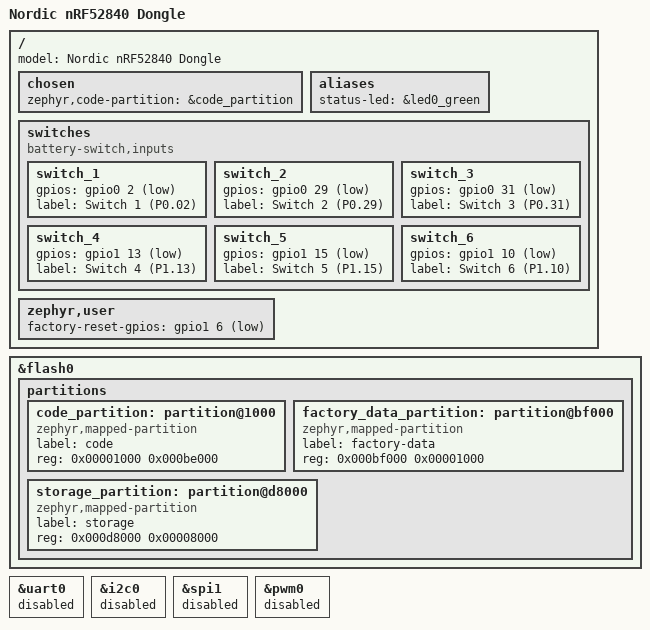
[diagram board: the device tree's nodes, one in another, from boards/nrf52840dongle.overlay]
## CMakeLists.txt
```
#
# SPDX-License-Identifier: MIT
#

cmake_minimum_required(VERSION 3.20.0)

find_package(Zephyr HINTS $ENV{ZEPHYR_BASE})

project(battery-switch)

target_include_directories(app PRIVATE src)

# Board name (devicetree model), shown as the hardware version by Matter
# controllers. Root node properties aren't exported to CMake, so it is read
# from the generated devicetree.
file(STRINGS ${ZEPHYR_DTS} board_model REGEX "^\tmodel = \"" LIMIT_COUNT 1)
string(REGEX REPLACE "^\tmodel = \"([^\"]*)\".*" "\\1" board_model "${board_model}")
target_compile_definitions(app PRIVATE "APP_BOARD_NAME=\"${board_model}\"")

# Transport-independent core: switch inputs, gesture detection, battery, LED.
target_sources(app PRIVATE
  src/main.c
  src/core/app_loop.c
  src/core/battery.c
  src/core/reset_pin.c
  src/core/switch_config.c
  src/core/status_led.c
  src/core/switch_gesture.c
  src/core/switch_input.c
)

target_sources_ifdef(CONFIG_APP_USB_INFO app PRIVATE
  src/core/usb_info.c
  src/third_party/qrcodegen/qrcodegen.c
)
target_sources_ifdef(CONFIG_APP_USB_BOOTLOADER_RESET app PRIVATE src/core/usb_bootloader.c)
target_sources_ifdef(CONFIG_APP_TRANSPORT_BLE app PRIVATE src/transport/ble/ble_transport.c)

if(CONFIG_APP_TRANSPORT_MATTER)
  include(${ZEPHYR_CONNECTEDHOMEIP_MODULE_DIR}/config/nrfconnect/app/enable-gnu-std.cmake)
  include(${ZEPHYR_NRF_MODULE_DIR}/samples/matter/common/cmake/data_model.cmake)
  include(${ZEPHYR_NRF_MODULE_DIR}/samples/matter/common/cmake/zap_helpers.cmake)
  ncs_get_zap_parent_dir(ZAP_PARENT_DIR)

  # Only the parts of the nRF Matter sample commons that do not depend on the
  # DK buttons/LEDs library.
  set(MATTER_COMMONS_SRC_DIR ${ZEPHYR_NRF_MODULE_DIR}/samples/matter/common/src)

  target_include_directories(app PRIVATE
    ${MATTER_COMMONS_SRC_DIR}
    ${ZAP_PARENT_DIR}
  )

  target_sources(app PRIVATE
    ${MATTER_COMMONS_SRC_DIR}/app/matter_init.cpp
    ${MATTER_COMMONS_SRC_DIR}/app/matter_event_handler.cpp
    ${MATTER_COMMONS_SRC_DIR}/clusters/cluster_init.cpp
    src/transport/matter/matter_transport.cpp
  )
  target_sources_ifdef(CONFIG_CHIP_FACTORY_DATA app PRIVATE src/transport/matter/self_provision.cpp)

  zephyr_linker_sources(SECTIONS ${MATTER_COMMONS_SRC_DIR}/clusters/cluster_init.ld)

  ncs_configure_data_model()
endif()
```

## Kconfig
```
#
# SPDX-License-Identifier: MIT
#

mainmenu "Battery powered switch"

menu "Battery switch application"

choice APP_TRANSPORT
	prompt "Radio transport"
	default APP_TRANSPORT_MATTER
	help
	  Selects the protocol used to report switch events and battery state.
	  The switch/battery core in src/core does not depend on the transport;
	  a new transport only has to implement src/transport/transport.h.

config APP_TRANSPORT_MATTER
	bool "Matter over Thread"
	help
	  Requires SB_CONFIG_MATTER=y in sysbuild.conf. Every switch is exposed
	  as a Generic Switch endpoint (1..6), the battery as a Power Source
	  cluster on endpoint 0.

config APP_TRANSPORT_BLE
	bool "Bluetooth LE (GATT)"
	select BT
	select BT_PERIPHERAL
	select BT_BAS
	select REBOOT
	help
	  Connectable peripheral that notifies switch events over a custom
	  GATT service, battery level over the Battery Service. Mainly for
	  testing without a Thread network; see src/transport/ble/ and
	  tools/ble_test_client.py. Build with -DFILE_SUFFIX=ble.

endchoice

config APP_BLE_ADV_INTERVAL_MS
	int "BLE advertising interval [ms]"
	depends on APP_TRANSPORT_BLE
	default 1000
	range 20 10000

menu "Switch inputs"

config APP_DEBOUNCE_MS
	int "Momentary switch: debounce time [ms]"
	default 20
	range 1 200

config APP_DEBOUNCE_LATCHING_MS
	int "Latching switch: debounce time [ms]"
	default 20
	range 1 500
	help
	  Debounce time for latching switches. They report every bounce
	  that outlasts the debounce time as an extra press, so noisy
	  contacts may need more than momentary switches. Nobody flips a
	  switch twice within 100 ms, so values up to that cost no
	  responsiveness.

config APP_LONG_PRESS_MS
	int "Momentary switch: hold time for a long press [ms]"
	default 1000
	range 200 10000

config APP_MULTI_PRESS_WINDOW_MS
	int "Momentary switch: max. gap between presses of a multi-press [ms]"
	default 400
	range 100 2000
	help
	  After the last release, MultiPressComplete is reported once no new
	  press started within this window. Larger values make double presses
	  easier, but delay the single press report by the same amount.

config APP_MULTI_PRESS_MAX
	int "Momentary switch: maximum number of presses in a multi-press"
	default 2
	range 2 10

config APP_LATCH_POLL_INTERVAL_MS
	int "Latching switch: poll interval while the switch is closed [ms]"
	default 100
	range 10 2000
	help
	  A closed switch would permanently draw current through the pull-up
	  resistor (~230 uA at 3 V with the internal 13 kOhm pull-up). While a
	  latching switch is closed, its pin is
	  disconnected and only briefly sampled at this interval. This is the
	  worst case latency for detecting the switch being opened.

config APP_LATCH_POLL_SETTLE_US
	int "Latching switch: pull-up settle time before sampling [us]"
	default 10
	range 1 1000
	help
	  Increase for long cables between the board and the switch.

endmenu

menu "Battery"

choice APP_BATTERY_TYPE
	prompt "Battery type"
	default APP_BATTERY_2XAAA_ALKALINE
	help
	  Selects the voltage-to-charge curve used for the reported battery
	  percentage. The battery is expected to be connected to the 3V3 pin
	  (the nRF52840 supply), so no voltage divider is needed.

config APP_BATTERY_CR2032
	bool "CR2032 lithium coin cell (3 V)"

config APP_BATTERY_2XAAA_ALKALINE
	bool "2x AAA alkaline in series"

config APP_BATTERY_2XAAA_CARBON_ZINC
	bool "2x AAA carbon-zinc in series"

config APP_BATTERY_2XAAA_NIMH
	bool "2x AAA NiMH in series"

endchoice

config APP_BATTERY_MEASURE_INTERVAL_S
	int "Battery measurement interval [s]"
	default 3600
	range 60 86400

config APP_BATTERY_WARNING_PERCENT
	int "Report charge level 'Warning' at or below [%]"
	default 20
	range 0 100

config APP_BATTERY_CRITICAL_PERCENT
	int "Report charge level 'Critical' (replace battery) at or below [%]"
	default 5
	range 0 100

endmenu

menu "User interface"

config APP_STATUS_LED
	bool "Status LED"
	default y
	help
	  Uses the devicetree alias 'status-led' for pairing, identify and
	  factory reset feedback. Blinks are short to save power.

config APP_BOOT_FLASHES
	int "Status LED: flashes at startup"
	depends on APP_STATUS_LED
	default 3
	range 0 10
	help
	  Quick flashes when the firmware starts, as a sign of life after
	  inserting the battery or flashing. 0 disables them.

config APP_PRODUCT_NAME
	string "Product name shown on the USB serial port"
	default "Battery Switch"

config APP_USB_INFO
	bool "Show the pairing code on the USB serial port"
	depends on USBD_CDC_ACM_CLASS && UART_LINE_CTRL
	depends on !CDC_ACM_SERIAL_INITIALIZE_AT_BOOT
	default y
	help
	  When a terminal opens the USB serial port, print the pairing code
	  and QR code. USB is only enabled while USB power is present, so it
	  costs no current on battery. Not available with the USB console
	  (usb-logging.conf), which logs the pairing code instead.

config APP_FACTORY_RESET_HOLD_MS
	int "Reset pad: hold time for factory reset [ms]"
	default 5000
	range 1000 60000
	help
	  The factory reset pad (devicetree: `factory-reset-gpios` in the
	  `zephyr,user` node) has to be held to GND continuously for this
	  long. The pad is separate from the switch inputs, so no switch
	  gesture can trigger a reset.

endmenu

config APP_USB_BOOTLOADER_RESET
	bool "Reboot into the bootloader on a 1200 baud USB touch"
	depends on USB_DEVICE_STACK_NEXT && UART_LINE_CTRL
	help
	  Development helper for builds with the USB console
	  (usb-logging.conf). Opening and closing the USB serial port at
	  1200 baud reboots into the Adafruit bootloader, so the board can be
	  reflashed without pressing reset.

choice APP_USB_BOOTLOADER_MODE
	prompt "Bootloader mode entered on a 1200 baud touch"
	depends on APP_USB_BOOTLOADER_RESET
	default APP_USB_BOOTLOADER_MODE_SERIAL

config APP_USB_BOOTLOADER_MODE_SERIAL
	bool "Serial DFU only"
	help
	  For adafruit-nrfutil, which sends the touch itself:
	    adafruit-nrfutil dfu serial --touch 1200 --singlebank ...
	  More reliable than the USB drive on macOS, which can hang when
	  copying large UF2 files.

config APP_USB_BOOTLOADER_MODE_UF2
	bool "UF2 USB drive"

endchoice

config APP_EVENT_QUEUE_SIZE
	int "Application event queue size"
	default 16

endmenu

# Matter over Thread defaults (same pattern as the nRF Connect SDK Matter
# samples). They only take effect when CONFIG_CHIP is enabled.

# Sleepy end device: the radio is off except for polling the parent.
choice OPENTHREAD_NORDIC_LIBRARY_CONFIGURATION
	default OPENTHREAD_NORDIC_LIBRARY_MTD
endchoice

choice OPENTHREAD_DEVICE_TYPE
	default OPENTHREAD_MTD
endchoice

config CHIP_ENABLE_ICD_SUPPORT
	default y

config CHIP_ICD_LIT_SUPPORT
	default y

config CHIP_ICD_SIT_SLOW_POLL_LIMIT
	default 5000

config CHIP_ICD_REPORT_ON_ACTIVE_MODE
	default y

# 0 dBm is plenty for an end device next to its parent and keeps the TX peak
# current low, which matters for coin cells.
config OPENTHREAD_DEFAULT_TX_POWER
	default 0

source "$(ZEPHYR_CONNECTEDHOMEIP_MODULE_DIR)/config/nrfconnect/chip-module/Kconfig.features"
source "$(ZEPHYR_CONNECTEDHOMEIP_MODULE_DIR)/config/nrfconnect/chip-module/Kconfig.defaults"
source "$(ZEPHYR_NRF_MODULE_DIR)/samples/matter/common/src/Kconfig"

source "Kconfig.zephyr"
```

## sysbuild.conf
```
SB_CONFIG_MATTER=y
SB_CONFIG_PARTITION_MANAGER=n

# Barebones: no MCUboot and no Matter OTA. The board's Adafruit UF2 bootloader
# stays in place (see boards/xiao_ble.overlay and sysbuild.cmake).
SB_CONFIG_MATTER_OTA=n

# Don't generate factory data in the build: it would give every device the
# same, publicly known Matter test passcode (20202021). Each device gets its
# own credentials from tools/provision_device.py instead.
SB_CONFIG_MATTER_FACTORY_DATA_GENERATE=n
```

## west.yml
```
# West manifest for a workspace application.
#
#   west init -m https://github.com/<you>/nrf52840-battery-button --mr main battery-switch-ws
#   cd battery-switch-ws && west update
#
# This pulls nRF Connect SDK v3.4.1 (Zephyr, OpenThread, Matter) next to this repository.

manifest:
  version: "0.13"

  remotes:
    - name: ncs
      url-base: https://github.com/nrfconnect

  projects:
    - name: nrf
      remote: ncs
      repo-path: sdk-nrf
      revision: v3.4.1
      import: true

  self:
    path: nrf52840-battery-button
```

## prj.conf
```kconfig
#
# Low-power configuration (default). For logs over SEGGER RTT build with
#   west build ... -- -DEXTRA_CONF_FILE=debug.conf
#

# ---------------------------------------------------------------------------
# Matter
# ---------------------------------------------------------------------------
CONFIG_CHIP=y
CONFIG_CHIP_PROJECT_CONFIG="src/chip_project_config.h"
CONFIG_CHIP_DEVICE_PRODUCT_NAME="Battery Switch"
CONFIG_NCS_SAMPLE_MATTER_ZAP_FILE_PATH="${APPLICATION_CONFIG_DIR}/src/default_zap/battery_switch.zap"

# Test Vendor ID / Product ID (0xFFF1 / 0x8000). Replace for a real product.
CONFIG_CHIP_DEVICE_PRODUCT_ID=32768
CONFIG_STD_CPP17=y

# Start BLE commissioning advertising on boot while not commissioned.
# Afterwards, pressing any switch restarts it.
CONFIG_CHIP_ENABLE_PAIRING_AUTOSTART=y
CONFIG_CHIP_BLE_EXT_ADVERTISING=y
CONFIG_CHIP_BLE_ADVERTISING_DURATION=15

CONFIG_BT_DEVICE_NAME="MatterSwitch"
CONFIG_BT_DEVICE_NAME_MAX=18

# Onboarding credentials come from the factory data partition, written per
# device by tools/provision_device.py (not generated by the build).
CONFIG_CHIP_FACTORY_DATA=y
CONFIG_CHIP_FACTORY_DATA_BUILD=n

# First boot computes the SPAKE2+ verifier on the device
# (src/transport/matter/self_provision.cpp).
CONFIG_PSA_WANT_ALG_PBKDF2_HMAC=y
CONFIG_PSA_WANT_KEY_TYPE_PASSWORD=y
CONFIG_PSA_WANT_KEY_TYPE_SPAKE2P_KEY_PAIR_DERIVE=y
CONFIG_PSA_WANT_KEY_TYPE_SPAKE2P_KEY_PAIR_EXPORT=y

# No MCUboot (see sysbuild.conf).
CONFIG_CHIP_BOOTLOADER_NONE=y

# The XIAO has no NFC antenna.
CONFIG_CHIP_NFC_ONBOARDING_PAYLOAD=n

# Parts of the nRF Matter sample commons that are not used.
CONFIG_NCS_SAMPLE_MATTER_TEST_EVENT_TRIGGERS=n
CONFIG_CHIP_LIB_SHELL=n

# ---------------------------------------------------------------------------
# Hardware
# ---------------------------------------------------------------------------
CONFIG_GPIO=y
CONFIG_ADC=y
CONFIG_FLASH=y

# The board's UF2 output would contain only the application. sysbuild.cmake
# builds build/battery_switch.uf2 with the Matter factory data included.
CONFIG_BUILD_OUTPUT_UF2=n

# Link at the application partition from devicetree (0x26000/0x27000 on UF2
# bootloader boards). Not every board's UF2 target sets this.
CONFIG_USE_DT_CODE_PARTITION=y

# ---------------------------------------------------------------------------
# Power
# ---------------------------------------------------------------------------
CONFIG_PM_DEVICE=y
CONFIG_RAM_POWER_DOWN_LIBRARY=y

# USB serial port that only shows the pairing code (src/core/usb_info.c),
# not a console. USB is only enabled while USB power is present.
CONFIG_BOARD_SERIAL_BACKEND_CDC_ACM=n
CONFIG_SERIAL=y
CONFIG_USB_DEVICE_STACK_NEXT=y
CONFIG_USBD_CDC_ACM_CLASS=y
CONFIG_UART_LINE_CTRL=y
CONFIG_CONSOLE=n
CONFIG_UART_CONSOLE=n
CONFIG_USE_SEGGER_RTT=n
CONFIG_LOG=n
CONFIG_PRINTK=n
CONFIG_SHELL=n
CONFIG_OPENTHREAD_SHELL=n
CONFIG_BOOT_BANNER=n
CONFIG_NCS_BOOT_BANNER=n
CONFIG_THREAD_NAME=n

CONFIG_ASSERT_VERBOSE=n
CONFIG_ASSERT_NO_FILE_INFO=y
CONFIG_RESET_ON_FATAL_ERROR=y

# Reduce flash usage.
CONFIG_LTO=y
CONFIG_ISR_TABLES_LOCAL_DECLARATION=y
```

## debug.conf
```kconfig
#
# Debug overlay: logs and printk over SEGGER RTT (needs the SWD probe).
#   west build -b xiao_ble/nrf52840 --sysbuild -- -DEXTRA_CONF_FILE=debug.conf
#
CONFIG_LOG=y
CONFIG_PRINTK=y
CONFIG_CONSOLE=y
CONFIG_USE_SEGGER_RTT=y
CONFIG_RTT_CONSOLE=y
CONFIG_NCS_BOOT_BANNER=y
CONFIG_THREAD_NAME=y
CONFIG_RESET_ON_FATAL_ERROR=n
```

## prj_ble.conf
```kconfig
#
# Bluetooth LE transport (for testing without a Thread network):
#   west build -b xiao_ble/nrf52840 --sysbuild -- -DFILE_SUFFIX=ble
# This file replaces prj.conf and sysbuild_ble.conf replaces sysbuild.conf.
#

CONFIG_APP_TRANSPORT_BLE=y

CONFIG_BT_DEVICE_NAME="BatterySwitch"
# Appearance: Generic Remote Control.
CONFIG_BT_DEVICE_APPEARANCE=384
CONFIG_BT_MAX_CONN=1

# ---------------------------------------------------------------------------
# Hardware
# ---------------------------------------------------------------------------
CONFIG_GPIO=y
CONFIG_ADC=y
CONFIG_FLASH=y

# Switch types changed over BLE are stored in the settings partition.
CONFIG_FLASH_MAP=y
CONFIG_NVS=y
CONFIG_SETTINGS=y

# sysbuild.cmake builds build/battery_switch.uf2.
CONFIG_BUILD_OUTPUT_UF2=n

# Link at the application partition from devicetree (0x26000/0x27000 on UF2
# bootloader boards). Not every board's UF2 target sets this.
CONFIG_USE_DT_CODE_PARTITION=y

# ---------------------------------------------------------------------------
# Power
# ---------------------------------------------------------------------------
CONFIG_PM_DEVICE=y

# No USB console by default. Add usb-logging.conf/.overlay for development.
CONFIG_BOARD_SERIAL_BACKEND_CDC_ACM=n
CONFIG_SERIAL=n
CONFIG_CONSOLE=n
CONFIG_UART_CONSOLE=n
CONFIG_USE_SEGGER_RTT=n
CONFIG_LOG=n
CONFIG_PRINTK=n
CONFIG_BOOT_BANNER=n
CONFIG_NCS_BOOT_BANNER=n

CONFIG_ASSERT_VERBOSE=n
CONFIG_ASSERT_NO_FILE_INFO=y
CONFIG_RESET_ON_FATAL_ERROR=y
```

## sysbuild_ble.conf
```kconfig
# Bluetooth LE build: no Matter, no factory data, no bootloader besides the
# board's UF2 bootloader.
SB_CONFIG_PARTITION_MANAGER=n
```

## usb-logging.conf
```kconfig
#
# Development overlay: log to the USB serial port and allow reflashing via a
# 1200 baud touch:
#   west build ... -- -DEXTRA_CONF_FILE=usb-logging.conf
# USB draws power; not for battery operation.
#
CONFIG_BOARD_SERIAL_BACKEND_CDC_ACM=y
CONFIG_SERIAL=y
CONFIG_CONSOLE=y
CONFIG_UART_CONSOLE=y
CONFIG_UART_LINE_CTRL=y
CONFIG_LOG=y
CONFIG_PRINTK=y
CONFIG_NCS_BOOT_BANNER=y
CONFIG_RESET_ON_FATAL_ERROR=n
CONFIG_APP_USB_BOOTLOADER_RESET=y
```

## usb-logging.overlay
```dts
/* Re-enable USB for usb-logging.conf (the board overlay disables it). */
&usbd {
	status = "okay";
};
```

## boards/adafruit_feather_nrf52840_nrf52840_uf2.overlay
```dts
/*
 * SPDX-License-Identifier: MIT
 *
 * Adafruit Feather nRF52840 Express: adafruit_feather_nrf52840/nrf52840/uf2.
 * The image also runs on the Feather nRF52840 Sense (same pins, the blue
 * LED is the same). Build-tested only.
 *
 * Switch wiring: every switch goes between its pin and GND.
 *
 *   Switch 1 -> A0 (P0.04)      Switch 4 -> A3 (P0.28)
 *   Switch 2 -> A1 (P0.05)      Switch 5 -> A4 (P0.02)
 *   Switch 3 -> A2 (P0.30)      Switch 6 -> A5 (P0.03)
 *
 * Factory reset: hold the board's USER button for 5 s.
 *
 * Battery: connect + to 3V and - to GND (2x AAA or CR2032), not to the LiPo
 * connector: the battery voltage is measured on the nRF52840 VDD rail.
 */

/ {
	aliases {
		status-led = &led1; /* blue */
	};

	switches {
		compatible = "battery-switch,inputs";

		switch_1 {
			gpios = <&gpio0 4 (GPIO_PULL_UP | GPIO_ACTIVE_LOW)>;
			label = "Switch 1 (A0)";
		};

		switch_2 {
			gpios = <&gpio0 5 (GPIO_PULL_UP | GPIO_ACTIVE_LOW)>;
			label = "Switch 2 (A1)";
		};

		switch_3 {
			gpios = <&gpio0 30 (GPIO_PULL_UP | GPIO_ACTIVE_LOW)>;
			label = "Switch 3 (A2)";
		};

		switch_4 {
			gpios = <&gpio0 28 (GPIO_PULL_UP | GPIO_ACTIVE_LOW)>;
			label = "Switch 4 (A3)";
		};

		switch_5 {
			gpios = <&gpio0 2 (GPIO_PULL_UP | GPIO_ACTIVE_LOW)>;
			label = "Switch 5 (A4)";
		};

		switch_6 {
			gpios = <&gpio0 3 (GPIO_PULL_UP | GPIO_ACTIVE_LOW)>;
			label = "Switch 6 (A5)";
		};
	};

	zephyr,user {
		/* USER button (P1.02), inside the enclosure. */
		factory-reset-gpios = <&gpio1 2 (GPIO_PULL_UP | GPIO_ACTIVE_LOW)>;
	};
};

/* The Feather ships with SoftDevice S140 v6: the application starts at 0x26000. */
#define UF2_APP_START 0x26000
#include "uf2_matter_layout.dtsi"

/* Peripherals that are not used; disabling them avoids idle current. */
&uart0 {
	status = "disabled";
};

&i2c0 {
	status = "disabled";
};

&spi1 {
	status = "disabled";
};

#include "battery_switch_common.dtsi"
```

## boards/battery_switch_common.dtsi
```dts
/*
 * SPDX-License-Identifier: MIT
 *
 * Parts shared by all board overlays. Include it at the end of the overlay.
 */

#include <zephyr/dt-bindings/adc/nrf-saadc.h>

/ {
	zephyr,user {
		io-channels = <&adc 0>;
	};
};

/* Battery voltage = nRF52840 VDD (battery connected to the 3V3 pin). */
&adc {
	#address-cells = <1>;
	#size-cells = <0>;
	status = "okay";

	channel@0 {
		reg = <0>;
		zephyr,gain = "ADC_GAIN_1_6";
		zephyr,reference = "ADC_REF_INTERNAL";
		zephyr,acquisition-time = <ADC_ACQ_TIME(ADC_ACQ_TIME_MICROSECONDS, 10)>;
		zephyr,input-positive = <NRF_SAADC_VDD>;
		zephyr,resolution = <12>;
		zephyr,oversampling = <4>;
	};
};

/*
 * USB serial port showing the pairing code (src/core/usb_info.c). USB is
 * only enabled while USB power is present. The output fits into the TX
 * FIFO, so a terminal that stops reading can't block the application.
 */
&board_cdc_acm_uart {
	tx-fifo-size = <2048>;
	rx-fifo-size = <64>;
};
```

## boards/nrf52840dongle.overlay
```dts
/*
 * SPDX-License-Identifier: MIT
 *
 * Nordic nRF52840 Dongle (PCA10059): nrf52840dongle/nrf52840.
 * Advanced, at your own risk: build-tested only, and not part of the
 * release builds.
 *
 * The dongle has Nordic's USB DFU bootloader instead of a UF2 bootloader:
 * flash the .hex with nRF Connect Programmer or nrfutil, see "nRF52840 Dongle
 * (advanced)" in the README.
 *
 * Switch wiring: every switch goes between its pad and GND. The pads are
 * labelled with their pin numbers on the dongle.
 *
 *   Switch 1 -> 0.02 (P0.02)      Switch 4 -> 1.13 (P1.13)
 *   Switch 2 -> 0.29 (P0.29)      Switch 5 -> 1.15 (P1.15)
 *   Switch 3 -> 0.31 (P0.31)      Switch 6 -> 1.10 (P1.10)
 *
 * Factory reset: hold the SW1 button (P1.06) for 5 s.
 *
 * Battery: out of the box the dongle runs from USB 5 V (nRF52840 high
 * voltage mode). For 2x AAA or a CR2032 on VDD, change the solder bridges
 * for an external supply as described in the nRF52840 Dongle user guide.
 */

/ {
	/* Shown as the hardware version by Matter controllers. */
	model = "Nordic nRF52840 Dongle";

	chosen {
		zephyr,code-partition = &code_partition;
	};

	aliases {
		status-led = &led0_green;
	};

	switches {
		compatible = "battery-switch,inputs";

		switch_1 {
			gpios = <&gpio0 2 (GPIO_PULL_UP | GPIO_ACTIVE_LOW)>;
			label = "Switch 1 (P0.02)";
		};

		switch_2 {
			gpios = <&gpio0 29 (GPIO_PULL_UP | GPIO_ACTIVE_LOW)>;
			label = "Switch 2 (P0.29)";
		};

		switch_3 {
			gpios = <&gpio0 31 (GPIO_PULL_UP | GPIO_ACTIVE_LOW)>;
			label = "Switch 3 (P0.31)";
		};

		switch_4 {
			gpios = <&gpio1 13 (GPIO_PULL_UP | GPIO_ACTIVE_LOW)>;
			label = "Switch 4 (P1.13)";
		};

		switch_5 {
			gpios = <&gpio1 15 (GPIO_PULL_UP | GPIO_ACTIVE_LOW)>;
			label = "Switch 5 (P1.15)";
		};

		switch_6 {
			gpios = <&gpio1 10 (GPIO_PULL_UP | GPIO_ACTIVE_LOW)>;
			label = "Switch 6 (P1.10)";
		};
	};

	zephyr,user {
		/* SW1 button on the dongle. */
		factory-reset-gpios = <&gpio1 6 (GPIO_PULL_UP | GPIO_ACTIVE_LOW)>;
	};
};

/*
 * Flash layout for the dongle's Nordic bootloader (no MCUboot):
 *
 *   0x00000 - 0x00FFF  MBR
 *   0x01000 - 0xBEFFF  application (760 KiB)
 *   0xBF000 - 0xBFFFF  Matter factory data (same address as on UF2 boards)
 *   0xC0000 - 0xD7FFF  unused
 *   0xD8000 - 0xDFFFF  settings, directly below the bootloader
 *   0xE0000 - 0xFFFFF  Nordic USB bootloader and its settings
 *
 * The bootloader updates the application in place (it is too large for the
 * bootloader's dual-bank mode), so the factory data and settings survive
 * firmware updates.
 */
/delete-node/ &boot_partition;
/delete-node/ &slot0_partition;
/delete-node/ &slot1_partition;
/delete-node/ &storage_partition;

&flash0 {
	partitions {
		code_partition: partition@1000 {
			compatible = "zephyr,mapped-partition";
			label = "code";
			reg = <0x00001000 0x000be000>;
		};

		factory_data_partition: partition@bf000 {
			compatible = "zephyr,mapped-partition";
			label = "factory-data";
			reg = <0x000bf000 0x00001000>;
		};

		storage_partition: partition@d8000 {
			compatible = "zephyr,mapped-partition";
			label = "storage";
			reg = <0x000d8000 0x00008000>;
		};
	};
};

/* Peripherals that are not used; disabling them avoids idle current. */
&uart0 {
	status = "disabled";
};

&i2c0 {
	status = "disabled";
};

&spi1 {
	status = "disabled";
};

&pwm0 {
	status = "disabled";
};

#include "battery_switch_common.dtsi"
```

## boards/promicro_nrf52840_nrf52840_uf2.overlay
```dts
/*
 * SPDX-License-Identifier: MIT
 *
 * Pro Micro nRF52840 and compatibles (nice!nano, SuperMini nRF52840, ...):
 * promicro_nrf52840/nrf52840/uf2. Build-tested only.
 *
 * Switch wiring: every switch goes between its pin and GND.
 *
 *   Switch 1 -> 017 (P0.17, "D2")    Switch 4 -> 024 (P0.24, "D5")
 *   Switch 2 -> 020 (P0.20, "D3")    Switch 5 -> 100 (P1.00, "D6")
 *   Switch 3 -> 022 (P0.22, "D4")    Switch 6 -> 011 (P0.11, "D7")
 *
 * Factory reset: hold 106 (P1.06, "D9") to GND for 5 s.
 *
 * Battery: connect + to VCC (3.3 V pin) and - to GND (2x AAA or CR2032), not
 * to B+/RAW: the battery voltage is measured on the nRF52840 VDD rail.
 */

/ {
	aliases {
		status-led = &led0;
	};

	switches {
		compatible = "battery-switch,inputs";

		switch_1 {
			gpios = <&gpio0 17 (GPIO_PULL_UP | GPIO_ACTIVE_LOW)>;
			label = "Switch 1 (P0.17)";
		};

		switch_2 {
			gpios = <&gpio0 20 (GPIO_PULL_UP | GPIO_ACTIVE_LOW)>;
			label = "Switch 2 (P0.20)";
		};

		switch_3 {
			gpios = <&gpio0 22 (GPIO_PULL_UP | GPIO_ACTIVE_LOW)>;
			label = "Switch 3 (P0.22)";
		};

		switch_4 {
			gpios = <&gpio0 24 (GPIO_PULL_UP | GPIO_ACTIVE_LOW)>;
			label = "Switch 4 (P0.24)";
		};

		switch_5 {
			gpios = <&gpio1 0 (GPIO_PULL_UP | GPIO_ACTIVE_LOW)>;
			label = "Switch 5 (P1.00)";
		};

		switch_6 {
			gpios = <&gpio0 11 (GPIO_PULL_UP | GPIO_ACTIVE_LOW)>;
			label = "Switch 6 (P0.11)";
		};
	};

	zephyr,user {
		factory-reset-gpios = <&gpio1 6 (GPIO_PULL_UP | GPIO_ACTIVE_LOW)>;
	};
};

/* These boards ship with SoftDevice S140 v6: the application starts at 0x26000. */
#define UF2_APP_START 0x26000
#include "uf2_matter_layout.dtsi"

/* The board's default peripherals use the switch pins; none are needed. */
&uart0 {
	status = "disabled";
};

&i2c0 {
	status = "disabled";
};

&i2c1 {
	status = "disabled";
};

&spi2 {
	status = "disabled";
};

&pwm0 {
	status = "disabled";
};

#include "battery_switch_common.dtsi"
```

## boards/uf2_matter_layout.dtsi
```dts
/*
 * SPDX-License-Identifier: MIT
 *
 * Flash layout for nRF52840 boards with the Adafruit UF2 bootloader.
 *
 * Define UF2_APP_START before including this file:
 *   0x27000  boards shipped with SoftDevice S140 v7 (e.g. Seeed XIAO nRF52840)
 *   0x26000  boards shipped with SoftDevice S140 v6 (e.g. Adafruit Feather
 *            nRF52840, ItsyBitsy, Pro Micro nRF52840)
 * The bootloader's INFO_UF2.TXT shows the SoftDevice version.
 *
 * The board's UF2 layout (nrf52840_partition_uf2_sdv6/7.dtsi) is kept; only
 * the application partition is shortened so that the Matter factory data can
 * sit directly behind it:
 *
 *   UF2_APP_START - 0xBEFFF  application (608 KiB with S140 v7)
 *   0xBF000 - 0xBFFFF        Matter factory data
 *   0xC0000 - 0xEBFFF        unused
 *   0xEC000 - 0xF3FFF        settings storage (board layout)
 *   0xF4000 - 0xFFFFF        UF2 bootloader (board layout)
 *
 * Keeping the application and the factory data together makes them one
 * contiguous image of about 600 KiB, small enough for the bootloader's serial
 * DFU as well as for the UF2 drive. If the application ever outgrows its
 * partition, the link fails: move the factory data up (and this comment).
 */

#ifndef UF2_APP_START
#error "Define UF2_APP_START (0x26000 or 0x27000) before including uf2_matter_layout.dtsi"
#endif

#define UF2_FACTORY_DATA_START 0xbf000

&code_partition {
	reg = <UF2_APP_START (UF2_FACTORY_DATA_START - UF2_APP_START)>;
};

&flash0 {
	partitions {
		factory_data_partition: partition@bf000 {
			label = "factory-data";
			reg = <UF2_FACTORY_DATA_START 0x1000>;
		};
	};
};
```

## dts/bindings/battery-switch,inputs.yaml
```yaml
description: |
  External switches connected to GPIO inputs.

  Each child node is one switch. The first child is switch 1 (Matter
  endpoint 1), the second child is switch 2 and so on; up to 6 switches are
  supported. Wire each switch between the GPIO pin and GND and use
  (GPIO_PULL_UP | GPIO_ACTIVE_LOW) as flags.

compatible: "battery-switch,inputs"

child-binding:
  description: A single external switch.
  properties:
    gpios:
      type: phandle-array
      required: true
    label:
      type: string
      description: Human readable name, only used for logging.
    switch-type:
      type: string
      default: "momentary"
      enum:
        - "momentary"
        - "latching"
      description: |
        Default type of the switch; it can be changed later from the smart
        home app (Matter Mode Select "Switch type").

        momentary:
          Push button, closed only while held. Reports press, release,
          long press and multi press.

        latching:
          Rocker or toggle switch, including plain-faced rockers (Panasonic
          Deco Lite, older Panasonic/National/Jimbo module switches) and
          switches that look like push buttons but latch (Schneider ZenCelo,
          Panasonic Cosmo Art, Rinsa, Glatima). Every change of position is
          reported as a short press, so controllers can use it like a push
          button. Changing it several times quickly counts as a multi press.
          Long press is not possible.
```

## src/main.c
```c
/*
 * SPDX-License-Identifier: MIT
 *
 * Battery powered switch: up to 6 external momentary or latching switches.
 *
 * Everything the application does happens in this loop: interrupts and
 * timers only post events. Between events the CPU sleeps.
 */

#include "core/app_loop.h"
#include "core/battery.h"
#include "core/reset_pin.h"
#include "core/switch_config.h"
#include "core/status_led.h"
#include "core/usb_info.h"
#include "core/switch_gesture.h"
#include "core/switch_input.h"
#include "transport/transport.h"

#include <zephyr/device.h>
#include <zephyr/devicetree.h>
#include <zephyr/kernel.h>
#include <zephyr/logging/log.h>
#include <zephyr/pm/device.h>

LOG_MODULE_REGISTER(main, CONFIG_LOG_DEFAULT_LEVEL);

static void battery_timer_expiry(struct k_timer *timer)
{
	app_loop_post(APP_EVT_BATTERY, 0, 0);
}

static K_TIMER_DEFINE(battery_timer, battery_timer_expiry, NULL);

/* Called when the reset pad has been held to GND for CONFIG_APP_FACTORY_RESET_HOLD_MS. */
static void factory_reset(void)
{
	LOG_WRN("Factory reset");
	status_led_flash(5);
	transport_factory_reset();
}

static void on_switch_event(uint8_t index, const struct switch_event *evt)
{
	transport_switch_event(index, evt);
}

static void on_input(uint8_t index, bool active)
{
	/* Any switch activity makes an unprovisioned device discoverable again. */
	if (!transport_is_provisioned()) {
		transport_start_pairing();
	}

	switch_gesture_input(index, active);
}

/* Change requested through the transport (e.g. the smart home app). */
static void change_switch_type(uint8_t index, uint16_t type)
{
	if (index >= switch_input_count() || !switch_type_is_valid(type) ||
	    switch_input_get_type(index) == type) {
		return;
	}

	switch_gesture_reset(index);
	switch_input_set_type(index, type);

	int err = switch_config_save(index, type);

	if (err) {
		LOG_ERR("Saving switch %u type failed (%d)", index + 1, err);
	}

	transport_switch_type_changed(index, type, switch_input_is_active(index));
}

/* A terminal opened the USB serial port. */
static void show_pairing_info(void)
{
#ifdef CONFIG_APP_USB_INFO
	usb_info_print();
#else
	/* Development builds with the USB console (usb-logging.conf) print it there. */
	struct transport_pairing_info info = { 0 };

	transport_get_pairing_info(&info);
	printk("Serial number %s, pairing code %s, QR code %s\n", info.serial, info.code, info.qr);
#endif
}

static void measure_battery(void)
{
	struct battery_state state;

	if (battery_measure(&state) == 0) {
		transport_battery_update(&state);
	}
}

static void suspend_external_flash(void)
{
	/*
	 * Boards like the XIAO and the Feather have a 2 MB QSPI flash that is
	 * not used. Put it into deep power-down, otherwise it idles in standby
	 * and wastes current.
	 */
#if defined(CONFIG_NORDIC_QSPI_NOR) && defined(CONFIG_PM_DEVICE) &&                                \
	DT_HAS_COMPAT_STATUS_OKAY(nordic_qspi_nor)
	const struct device *flash = DEVICE_DT_GET(DT_COMPAT_GET_ANY_STATUS_OKAY(nordic_qspi_nor));

	if (device_is_ready(flash)) {
		(void)pm_device_action_run(flash, PM_DEVICE_ACTION_SUSPEND);
	}
#endif
}

int main(void)
{
	struct transport_switch_config switches = { 0 };
	int err;

	suspend_external_flash();

	err = status_led_init();
	if (err) {
		LOG_WRN("Status LED init failed (%d)", err);
	}
#if CONFIG_APP_BOOT_FLASHES > 0
	status_led_flash(CONFIG_APP_BOOT_FLASHES);
#endif

	err = battery_init();
	if (err) {
		LOG_WRN("Battery measurement init failed (%d)", err);
	}

	err = switch_input_init(on_input);
	if (err) {
		LOG_ERR("Switch input init failed (%d)", err);
		return err;
	}

	err = switch_config_load();
	if (err) {
		LOG_WRN("Loading switch types failed (%d), using defaults", err);
	}

	switches.count = switch_input_count();
	for (uint8_t i = 0; i < switches.count; i++) {
		switches.type[i] = switch_input_get_type(i);
		switches.active[i] = switch_input_is_active(i);
	}

	switch_gesture_init(switches.count, on_switch_event);

	err = transport_init(&switches, battery_get_info());
	if (err) {
		LOG_ERR("Transport init failed (%d)", err);
		return err;
	}

	err = reset_pin_init(factory_reset);
	if (err) {
		LOG_WRN("No factory reset pad (%d)", err);
	}

#ifdef CONFIG_APP_USB_INFO
	err = usb_info_init();
	if (err) {
		LOG_WRN("USB init failed (%d)", err);
	}
#endif

	measure_battery();
	k_timer_start(&battery_timer, K_SECONDS(CONFIG_APP_BATTERY_MEASURE_INTERVAL_S),
		      K_SECONDS(CONFIG_APP_BATTERY_MEASURE_INTERVAL_S));

	for (;;) {
		struct app_evt evt;

		app_loop_wait(&evt);

		switch (evt.type) {
		case APP_EVT_INPUT_IRQ:
		case APP_EVT_INPUT_DEBOUNCE:
		case APP_EVT_INPUT_POLL:
			switch_input_process(&evt);
			break;
		case APP_EVT_GESTURE_TIMER:
			switch_gesture_process(&evt);
			break;
		case APP_EVT_SWITCH_TYPE:
			change_switch_type(evt.index, evt.arg);
			break;
		case APP_EVT_BATTERY:
			measure_battery();
			break;
		case APP_EVT_RESET_PIN:
		case APP_EVT_FACTORY_RESET_TIMER:
			reset_pin_process(&evt);
			break;
		case APP_EVT_USB_TERMINAL:
			show_pairing_info();
			break;
		default:
			break;
		}
	}

	return 0;
}
```

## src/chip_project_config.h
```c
/*
 * SPDX-License-Identifier: MIT
 *
 * Project specific overrides of the Matter (CHIP) configuration.
 */

#pragma once
```
